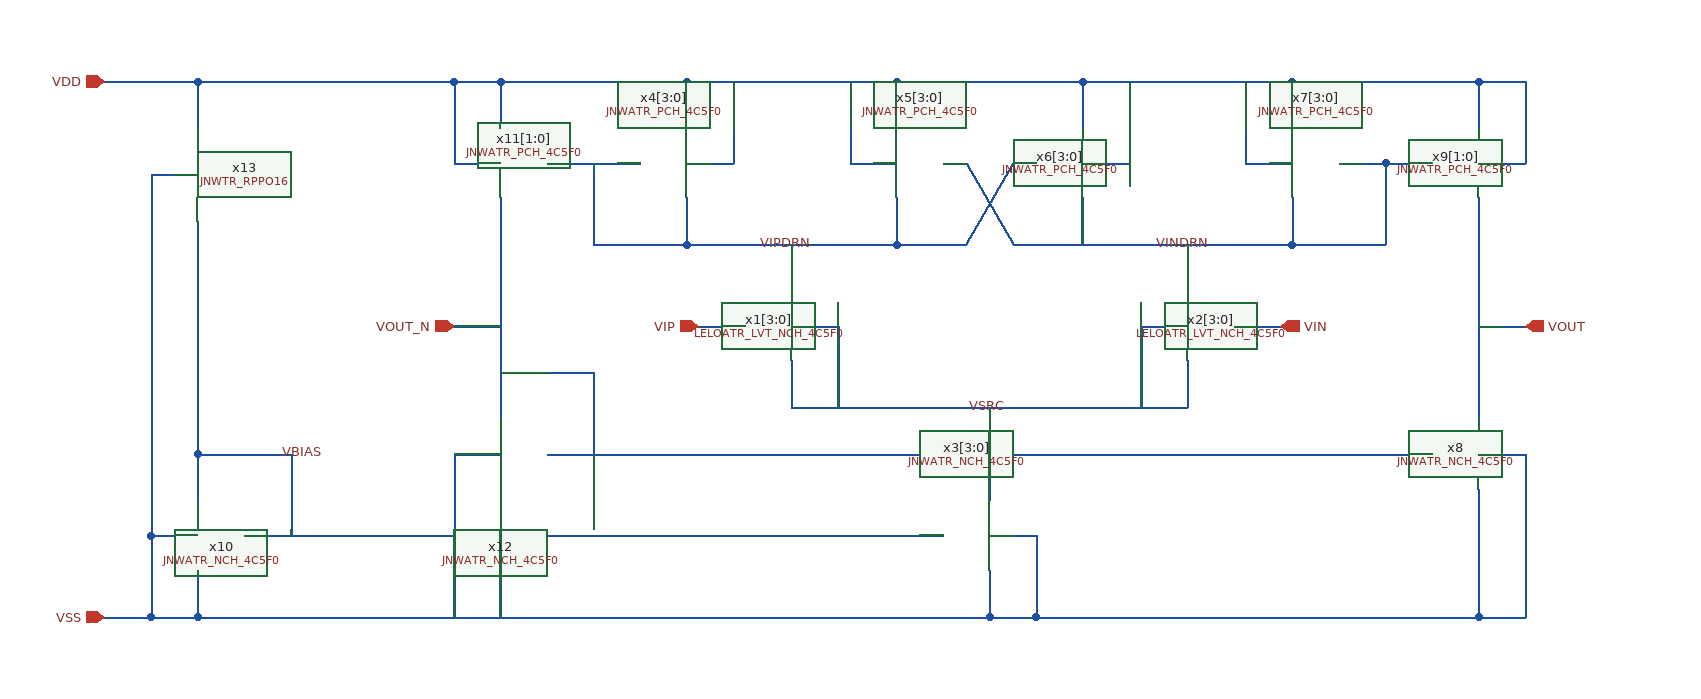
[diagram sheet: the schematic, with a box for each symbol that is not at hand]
v {xschem version=3.4.6 file_version=1.2}
G {}
K {}
V {}
S {}
E {}
N 520 180 560 180 {lab=VDD}
N 520 640 560 640 {lab=VSS}
N 1700 390 1740 390 {lab=VOUT}
N 600 300 600 500 {lab=VBIAS}
N 560 260 580 260 {lab=VSS}
N 560 180 600 180 {lab=VDD}
N 600 180 600 220 {lab=VDD}
N 560 570 600 570 {lab=VSS}
N 600 600 600 640 {lab=VSS}
N 560 640 600 640 {lab=VSS}
N 640 570 1240 570 {lab=VBIAS}
N 600 640 1280 640 {lab=VSS}
N 1280 600 1280 640 {lab=VSS}
N 1110 420 1110 460 {lab=VSRC}
N 1110 460 1450 460 {lab=VSRC}
N 1450 420 1450 460 {lab=VSRC}
N 1280 460 1280 540 {lab=VSRC}
N 1110 390 1150 390 {lab=VSRC}
N 1150 390 1150 460 {lab=VSRC}
N 1410 390 1450 390 {lab=VSRC}
N 1410 390 1410 460 {lab=VSRC}
N 1280 570 1320 570 {lab=VSS}
N 1320 570 1320 640 {lab=VSS}
N 1280 640 1320 640 {lab=VSS}
N 1200 280 1200 320 {lab=VIPDRN}
N 1450 320 1450 360 {lab=VINDRN}
N 1490 390 1530 390 {lab=VIN}
N 1030 390 1070 390 {lab=VIP}
N 1260 250 1300 320 {lab=VINDRN}
N 1360 250 1400 250 {lab=VDD}
N 1400 180 1400 250 {lab=VDD}
N 1020 250 1060 250 {lab=VDD}
N 1060 180 1060 250 {lab=VDD}
N 1200 180 1200 220 {lab=VDD}
N 1360 180 1360 220 {lab=VDD}
N 560 570 560 640 {lab=VSS}
N 560 260 560 570 {lab=VSS}
N 1040 320 1200 320 {lab=VIPDRN}
N 1260 320 1300 250 {lab=VIPDRN}
N 600 500 680 500 {lab=VBIAS}
N 680 500 680 570 {lab=VBIAS}
N 600 500 600 540 {lab=VBIAS}
N 1700 280 1700 470 {lab=VOUT}
N 1700 530 1700 640 {lab=VSS}
N 1320 640 1700 640 {lab=VSS}
N 1700 180 1700 220 {lab=VDD}
N 1700 250 1740 250 {lab=VDD}
N 1740 180 1740 250 {lab=VDD}
N 1700 180 1740 180 {lab=VDD}
N 1700 500 1740 500 {lab=VSS}
N 1740 500 1740 640 {lab=VSS}
N 1700 640 1740 640 {lab=VSS}
N 1240 250 1260 250 {lab=VINDRN}
N 1300 250 1320 250 {lab=VIPDRN}
N 1300 320 1520 320 {lab=VINDRN}
N 900 500 1660 500 {lab=VOUT_N}
N 820 390 860 390 {lab=VOUT_N}
N 860 280 860 470 {lab=VOUT_N}
N 860 530 860 640 {lab=VSS}
N 860 180 860 220 {lab=VDD}
N 820 250 860 250 {lab=VDD}
N 820 180 820 250 {lab=VDD}
N 820 180 860 180 {lab=VDD}
N 820 500 860 500 {lab=VSS}
N 820 500 820 640 {lab=VSS}
N 1110 320 1110 360 {lab=VIPDRN}
N 1020 320 1040 320 {lab=VIPDRN}
N 1520 320 1540 320 {lab=VINDRN}
N 1360 280 1360 320 {lab=VINDRN}
N 1540 180 1540 220 {lab=VDD}
N 1540 280 1540 320 {lab=VINDRN}
N 1020 280 1020 320 {lab=VIPDRN}
N 1020 180 1020 220 {lab=VDD}
N 940 320 1020 320 {lab=VIPDRN}
N 940 250 940 320 {lab=VIPDRN}
N 900 250 980 250 {lab=VIPDRN}
N 1540 320 1620 320 {lab=VINDRN}
N 1620 250 1620 320 {lab=VINDRN}
N 1620 250 1660 250 {lab=VINDRN}
N 1580 250 1620 250 {lab=VINDRN}
N 1200 320 1260 320 {lab=VIPDRN}
N 860 180 1020 180 {lab=VDD}
N 1020 180 1110 180 {lab=VDD}
N 1110 180 1200 180 {lab=VDD}
N 1200 180 1360 180 {lab=VDD}
N 1360 180 1450 180 {lab=VDD}
N 1450 180 1540 180 {lab=VDD}
N 1540 180 1700 180 {lab=VDD}
N 600 180 820 180 {lab=VDD}
N 1500 250 1540 250 {lab=VDD}
N 1500 180 1500 250 {lab=VDD}
N 1160 250 1200 250 {lab=VDD}
N 1160 180 1160 250 {lab=VDD}
N 940 430 940 500 {lab=VOUT_N}
N 860 430 940 430 {lab=VOUT_N}
C {devices/ipin.sym} 520 180 0 0 {name=p3 lab=VDD}
C {devices/ipin.sym} 520 640 0 0 {name=p4 lab=VSS}
C {devices/opin.sym} 1740 390 0 0 {name=p5 lab=VOUT
}
C {JNW_TR_SKY130A/JNWTR_RPPO16.sym} 600 220 1 0 {name=x13}
C {JNW_ATR_SKY130A/JNWATR_NCH_4C5F0.sym} 1240 570 0 0 {name=x3[3:0]}
C {JNW_ATR_SKY130A/JNWATR_NCH_4C5F0.sym} 640 570 0 1 {name=x10}
C {devices/ipin.sym} 1530 390 0 1 {name=p1 lab=VIN}
C {devices/ipin.sym} 1030 390 0 0 {name=p2 lab=VIP}
C {JNW_ATR_SKY130A/JNWATR_PCH_4C5F0.sym} 1240 250 0 1 {name=x5[3:0]}
C {JNW_ATR_SKY130A/JNWATR_PCH_4C5F0.sym} 1320 250 0 0 {name=x6[3:0]}
C {JNW_ATR_SKY130A/JNWATR_PCH_4C5F0.sym} 1580 250 0 1 {name=x7[3:0]}
C {JNW_ATR_SKY130A/JNWATR_NCH_4C5F0.sym} 1660 500 0 0 {name=x8}
C {devices/opin.sym} 820 390 0 1 {name=p6 lab=VOUT_N
}
C {JNW_ATR_SKY130A/JNWATR_PCH_4C5F0.sym} 900 250 0 1 {name=x11[1:0]}
C {JNW_ATR_SKY130A/JNWATR_NCH_4C5F0.sym} 900 500 0 1 {name=x12}
C {JNW_ATR_SKY130A/JNWATR_PCH_4C5F0.sym} 980 250 0 0 {name=x4[3:0]}
C {JNW_ATR_SKY130A/JNWATR_PCH_4C5F0.sym} 1660 250 0 0 {name=x9[1:0]}
C {devices/lab_wire.sym} 670 500 0 1 {name=p7 sig_type=std_logic lab=VBIAS}
C {devices/lab_wire.sym} 1260 460 0 1 {name=p8 sig_type=std_logic lab=VSRC}
C {devices/lab_wire.sym} 1080 320 0 1 {name=p9 sig_type=std_logic lab=VIPDRN}
C {devices/lab_wire.sym} 1420 320 0 1 {name=p10 sig_type=std_logic lab=VINDRN}
C {LELO_ATR_SKY130A/LELOATR_LVT_NCH_4C5F0.sym} 1070 390 0 0 {name=x1[3:0]}
C {LELO_ATR_SKY130A/LELOATR_LVT_NCH_4C5F0.sym} 1490 390 0 1 {name=x2[3:0]}
